##
## LEF for PtnCells ;
## created by Innovus v15.23-s045_1 on Sat Mar  7 15:15:52 2026
##

VERSION 5.8 ;

BUSBITCHARS "[]" ;
DIVIDERCHAR "/" ;

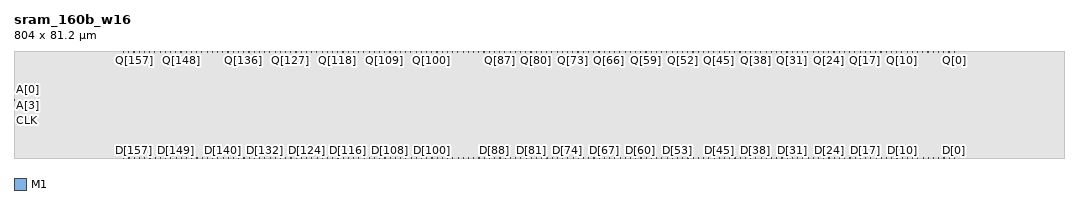
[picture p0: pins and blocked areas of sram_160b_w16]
MACRO sram_160b_w16
  CLASS BLOCK ;
  SIZE 804.0000 BY 81.2000 ;
  FOREIGN sram_160b_w16 0.0000 0.0000 ;
  ORIGIN 0 0 ;
  SYMMETRY X Y R90 ;
  PIN CLK
    DIRECTION INPUT ;
    USE SIGNAL ;
    PORT
      LAYER M1 ;
        RECT 0.0000 28.3550 0.4700 28.4450 ;
    END
  END CLK
  PIN D[159]
    DIRECTION INPUT ;
    USE SIGNAL ;
    PORT
      LAYER M1 ;
        RECT 84.0550 0.0000 84.1450 0.4700 ;
    END
  END D[159]
  PIN D[158]
    DIRECTION INPUT ;
    USE SIGNAL ;
    PORT
      LAYER M1 ;
        RECT 88.0550 0.0000 88.1450 0.4700 ;
    END
  END D[158]
  PIN D[157]
    DIRECTION INPUT ;
    USE SIGNAL ;
    PORT
      LAYER M1 ;
        RECT 92.0550 0.0000 92.1450 0.4700 ;
    END
  END D[157]
  PIN D[156]
    DIRECTION INPUT ;
    USE SIGNAL ;
    PORT
      LAYER M1 ;
        RECT 96.0550 0.0000 96.1450 0.4700 ;
    END
  END D[156]
  PIN D[155]
    DIRECTION INPUT ;
    USE SIGNAL ;
    PORT
      LAYER M1 ;
        RECT 100.0550 0.0000 100.1450 0.4700 ;
    END
  END D[155]
  PIN D[154]
    DIRECTION INPUT ;
    USE SIGNAL ;
    PORT
      LAYER M1 ;
        RECT 104.0550 0.0000 104.1450 0.4700 ;
    END
  END D[154]
  PIN D[153]
    DIRECTION INPUT ;
    USE SIGNAL ;
    PORT
      LAYER M1 ;
        RECT 108.0550 0.0000 108.1450 0.4700 ;
    END
  END D[153]
  PIN D[152]
    DIRECTION INPUT ;
    USE SIGNAL ;
    PORT
      LAYER M1 ;
        RECT 112.0550 0.0000 112.1450 0.4700 ;
    END
  END D[152]
  PIN D[151]
    DIRECTION INPUT ;
    USE SIGNAL ;
    PORT
      LAYER M1 ;
        RECT 116.0550 0.0000 116.1450 0.4700 ;
    END
  END D[151]
  PIN D[150]
    DIRECTION INPUT ;
    USE SIGNAL ;
    PORT
      LAYER M1 ;
        RECT 120.0550 0.0000 120.1450 0.4700 ;
    END
  END D[150]
  PIN D[149]
    DIRECTION INPUT ;
    USE SIGNAL ;
    PORT
      LAYER M1 ;
        RECT 124.0550 0.0000 124.1450 0.4700 ;
    END
  END D[149]
  PIN D[148]
    DIRECTION INPUT ;
    USE SIGNAL ;
    PORT
      LAYER M1 ;
        RECT 128.0550 0.0000 128.1450 0.4700 ;
    END
  END D[148]
  PIN D[147]
    DIRECTION INPUT ;
    USE SIGNAL ;
    PORT
      LAYER M1 ;
        RECT 132.0550 0.0000 132.1450 0.4700 ;
    END
  END D[147]
  PIN D[146]
    DIRECTION INPUT ;
    USE SIGNAL ;
    PORT
      LAYER M1 ;
        RECT 136.0550 0.0000 136.1450 0.4700 ;
    END
  END D[146]
  PIN D[145]
    DIRECTION INPUT ;
    USE SIGNAL ;
    PORT
      LAYER M1 ;
        RECT 140.0550 0.0000 140.1450 0.4700 ;
    END
  END D[145]
  PIN D[144]
    DIRECTION INPUT ;
    USE SIGNAL ;
    PORT
      LAYER M1 ;
        RECT 144.0550 0.0000 144.1450 0.4700 ;
    END
  END D[144]
  PIN D[143]
    DIRECTION INPUT ;
    USE SIGNAL ;
    PORT
      LAYER M1 ;
        RECT 148.0550 0.0000 148.1450 0.4700 ;
    END
  END D[143]
  PIN D[142]
    DIRECTION INPUT ;
    USE SIGNAL ;
    PORT
      LAYER M1 ;
        RECT 152.0550 0.0000 152.1450 0.4700 ;
    END
  END D[142]
  PIN D[141]
    DIRECTION INPUT ;
    USE SIGNAL ;
    PORT
      LAYER M1 ;
        RECT 156.0550 0.0000 156.1450 0.4700 ;
    END
  END D[141]
  PIN D[140]
    DIRECTION INPUT ;
    USE SIGNAL ;
    PORT
      LAYER M1 ;
        RECT 160.0550 0.0000 160.1450 0.4700 ;
    END
  END D[140]
  PIN D[139]
    DIRECTION INPUT ;
    USE SIGNAL ;
    PORT
      LAYER M1 ;
        RECT 164.0550 0.0000 164.1450 0.4700 ;
    END
  END D[139]
  PIN D[138]
    DIRECTION INPUT ;
    USE SIGNAL ;
    PORT
      LAYER M1 ;
        RECT 168.0550 0.0000 168.1450 0.4700 ;
    END
  END D[138]
  PIN D[137]
    DIRECTION INPUT ;
    USE SIGNAL ;
    PORT
      LAYER M1 ;
        RECT 172.0550 0.0000 172.1450 0.4700 ;
    END
  END D[137]
  PIN D[136]
    DIRECTION INPUT ;
    USE SIGNAL ;
    PORT
      LAYER M1 ;
        RECT 176.0550 0.0000 176.1450 0.4700 ;
    END
  END D[136]
  PIN D[135]
    DIRECTION INPUT ;
    USE SIGNAL ;
    PORT
      LAYER M1 ;
        RECT 180.0550 0.0000 180.1450 0.4700 ;
    END
  END D[135]
  PIN D[134]
    DIRECTION INPUT ;
    USE SIGNAL ;
    PORT
      LAYER M1 ;
        RECT 184.0550 0.0000 184.1450 0.4700 ;
    END
  END D[134]
  PIN D[133]
    DIRECTION INPUT ;
    USE SIGNAL ;
    PORT
      LAYER M1 ;
        RECT 188.0550 0.0000 188.1450 0.4700 ;
    END
  END D[133]
  PIN D[132]
    DIRECTION INPUT ;
    USE SIGNAL ;
    PORT
      LAYER M1 ;
        RECT 192.0550 0.0000 192.1450 0.4700 ;
    END
  END D[132]
  PIN D[131]
    DIRECTION INPUT ;
    USE SIGNAL ;
    PORT
      LAYER M1 ;
        RECT 196.0550 0.0000 196.1450 0.4700 ;
    END
  END D[131]
  PIN D[130]
    DIRECTION INPUT ;
    USE SIGNAL ;
    PORT
      LAYER M1 ;
        RECT 200.0550 0.0000 200.1450 0.4700 ;
    END
  END D[130]
  PIN D[129]
    DIRECTION INPUT ;
    USE SIGNAL ;
    PORT
      LAYER M1 ;
        RECT 204.0550 0.0000 204.1450 0.4700 ;
    END
  END D[129]
  PIN D[128]
    DIRECTION INPUT ;
    USE SIGNAL ;
    PORT
      LAYER M1 ;
        RECT 208.0550 0.0000 208.1450 0.4700 ;
    END
  END D[128]
  PIN D[127]
    DIRECTION INPUT ;
    USE SIGNAL ;
    PORT
      LAYER M1 ;
        RECT 212.0550 0.0000 212.1450 0.4700 ;
    END
  END D[127]
  PIN D[126]
    DIRECTION INPUT ;
    USE SIGNAL ;
    PORT
      LAYER M1 ;
        RECT 216.0550 0.0000 216.1450 0.4700 ;
    END
  END D[126]
  PIN D[125]
    DIRECTION INPUT ;
    USE SIGNAL ;
    PORT
      LAYER M1 ;
        RECT 220.0550 0.0000 220.1450 0.4700 ;
    END
  END D[125]
  PIN D[124]
    DIRECTION INPUT ;
    USE SIGNAL ;
    PORT
      LAYER M1 ;
        RECT 224.0550 0.0000 224.1450 0.4700 ;
    END
  END D[124]
  PIN D[123]
    DIRECTION INPUT ;
    USE SIGNAL ;
    PORT
      LAYER M1 ;
        RECT 228.0550 0.0000 228.1450 0.4700 ;
    END
  END D[123]
  PIN D[122]
    DIRECTION INPUT ;
    USE SIGNAL ;
    PORT
      LAYER M1 ;
        RECT 232.0550 0.0000 232.1450 0.4700 ;
    END
  END D[122]
  PIN D[121]
    DIRECTION INPUT ;
    USE SIGNAL ;
    PORT
      LAYER M1 ;
        RECT 236.0550 0.0000 236.1450 0.4700 ;
    END
  END D[121]
  PIN D[120]
    DIRECTION INPUT ;
    USE SIGNAL ;
    PORT
      LAYER M1 ;
        RECT 240.0550 0.0000 240.1450 0.4700 ;
    END
  END D[120]
  PIN D[119]
    DIRECTION INPUT ;
    USE SIGNAL ;
    PORT
      LAYER M1 ;
        RECT 244.0550 0.0000 244.1450 0.4700 ;
    END
  END D[119]
  PIN D[118]
    DIRECTION INPUT ;
    USE SIGNAL ;
    PORT
      LAYER M1 ;
        RECT 248.0550 0.0000 248.1450 0.4700 ;
    END
  END D[118]
  PIN D[117]
    DIRECTION INPUT ;
    USE SIGNAL ;
    PORT
      LAYER M1 ;
        RECT 252.0550 0.0000 252.1450 0.4700 ;
    END
  END D[117]
  PIN D[116]
    DIRECTION INPUT ;
    USE SIGNAL ;
    PORT
      LAYER M1 ;
        RECT 256.0550 0.0000 256.1450 0.4700 ;
    END
  END D[116]
  PIN D[115]
    DIRECTION INPUT ;
    USE SIGNAL ;
    PORT
      LAYER M1 ;
        RECT 260.0550 0.0000 260.1450 0.4700 ;
    END
  END D[115]
  PIN D[114]
    DIRECTION INPUT ;
    USE SIGNAL ;
    PORT
      LAYER M1 ;
        RECT 264.0550 0.0000 264.1450 0.4700 ;
    END
  END D[114]
  PIN D[113]
    DIRECTION INPUT ;
    USE SIGNAL ;
    PORT
      LAYER M1 ;
        RECT 268.0550 0.0000 268.1450 0.4700 ;
    END
  END D[113]
  PIN D[112]
    DIRECTION INPUT ;
    USE SIGNAL ;
    PORT
      LAYER M1 ;
        RECT 272.0550 0.0000 272.1450 0.4700 ;
    END
  END D[112]
  PIN D[111]
    DIRECTION INPUT ;
    USE SIGNAL ;
    PORT
      LAYER M1 ;
        RECT 276.0550 0.0000 276.1450 0.4700 ;
    END
  END D[111]
  PIN D[110]
    DIRECTION INPUT ;
    USE SIGNAL ;
    PORT
      LAYER M1 ;
        RECT 280.0550 0.0000 280.1450 0.4700 ;
    END
  END D[110]
  PIN D[109]
    DIRECTION INPUT ;
    USE SIGNAL ;
    PORT
      LAYER M1 ;
        RECT 284.0550 0.0000 284.1450 0.4700 ;
    END
  END D[109]
  PIN D[108]
    DIRECTION INPUT ;
    USE SIGNAL ;
    PORT
      LAYER M1 ;
        RECT 288.0550 0.0000 288.1450 0.4700 ;
    END
  END D[108]
  PIN D[107]
    DIRECTION INPUT ;
    USE SIGNAL ;
    PORT
      LAYER M1 ;
        RECT 292.0550 0.0000 292.1450 0.4700 ;
    END
  END D[107]
  PIN D[106]
    DIRECTION INPUT ;
    USE SIGNAL ;
    PORT
      LAYER M1 ;
        RECT 296.0550 0.0000 296.1450 0.4700 ;
    END
  END D[106]
  PIN D[105]
    DIRECTION INPUT ;
    USE SIGNAL ;
    PORT
      LAYER M1 ;
        RECT 300.0550 0.0000 300.1450 0.4700 ;
    END
  END D[105]
  PIN D[104]
    DIRECTION INPUT ;
    USE SIGNAL ;
    PORT
      LAYER M1 ;
        RECT 304.0550 0.0000 304.1450 0.4700 ;
    END
  END D[104]
  PIN D[103]
    DIRECTION INPUT ;
    USE SIGNAL ;
    PORT
      LAYER M1 ;
        RECT 308.0550 0.0000 308.1450 0.4700 ;
    END
  END D[103]
  PIN D[102]
    DIRECTION INPUT ;
    USE SIGNAL ;
    PORT
      LAYER M1 ;
        RECT 312.0550 0.0000 312.1450 0.4700 ;
    END
  END D[102]
  PIN D[101]
    DIRECTION INPUT ;
    USE SIGNAL ;
    PORT
      LAYER M1 ;
        RECT 316.0550 0.0000 316.1450 0.4700 ;
    END
  END D[101]
  PIN D[100]
    DIRECTION INPUT ;
    USE SIGNAL ;
    PORT
      LAYER M1 ;
        RECT 320.0550 0.0000 320.1450 0.4700 ;
    END
  END D[100]
  PIN D[99]
    DIRECTION INPUT ;
    USE SIGNAL ;
    PORT
      LAYER M1 ;
        RECT 324.0550 0.0000 324.1450 0.4700 ;
    END
  END D[99]
  PIN D[98]
    DIRECTION INPUT ;
    USE SIGNAL ;
    PORT
      LAYER M1 ;
        RECT 328.0550 0.0000 328.1450 0.4700 ;
    END
  END D[98]
  PIN D[97]
    DIRECTION INPUT ;
    USE SIGNAL ;
    PORT
      LAYER M1 ;
        RECT 332.0550 0.0000 332.1450 0.4700 ;
    END
  END D[97]
  PIN D[96]
    DIRECTION INPUT ;
    USE SIGNAL ;
    PORT
      LAYER M1 ;
        RECT 336.0550 0.0000 336.1450 0.4700 ;
    END
  END D[96]
  PIN D[95]
    DIRECTION INPUT ;
    USE SIGNAL ;
    PORT
      LAYER M1 ;
        RECT 340.0550 0.0000 340.1450 0.4700 ;
    END
  END D[95]
  PIN D[94]
    DIRECTION INPUT ;
    USE SIGNAL ;
    PORT
      LAYER M1 ;
        RECT 344.0550 0.0000 344.1450 0.4700 ;
    END
  END D[94]
  PIN D[93]
    DIRECTION INPUT ;
    USE SIGNAL ;
    PORT
      LAYER M1 ;
        RECT 348.0550 0.0000 348.1450 0.4700 ;
    END
  END D[93]
  PIN D[92]
    DIRECTION INPUT ;
    USE SIGNAL ;
    PORT
      LAYER M1 ;
        RECT 352.0550 0.0000 352.1450 0.4700 ;
    END
  END D[92]
  PIN D[91]
    DIRECTION INPUT ;
    USE SIGNAL ;
    PORT
      LAYER M1 ;
        RECT 356.0550 0.0000 356.1450 0.4700 ;
    END
  END D[91]
  PIN D[90]
    DIRECTION INPUT ;
    USE SIGNAL ;
    PORT
      LAYER M1 ;
        RECT 360.0550 0.0000 360.1450 0.4700 ;
    END
  END D[90]
  PIN D[89]
    DIRECTION INPUT ;
    USE SIGNAL ;
    PORT
      LAYER M1 ;
        RECT 364.0550 0.0000 364.1450 0.4700 ;
    END
  END D[89]
  PIN D[88]
    DIRECTION INPUT ;
    USE SIGNAL ;
    PORT
      LAYER M1 ;
        RECT 368.0550 0.0000 368.1450 0.4700 ;
    END
  END D[88]
  PIN D[87]
    DIRECTION INPUT ;
    USE SIGNAL ;
    PORT
      LAYER M1 ;
        RECT 372.0550 0.0000 372.1450 0.4700 ;
    END
  END D[87]
  PIN D[86]
    DIRECTION INPUT ;
    USE SIGNAL ;
    PORT
      LAYER M1 ;
        RECT 376.0550 0.0000 376.1450 0.4700 ;
    END
  END D[86]
  PIN D[85]
    DIRECTION INPUT ;
    USE SIGNAL ;
    PORT
      LAYER M1 ;
        RECT 380.0550 0.0000 380.1450 0.4700 ;
    END
  END D[85]
  PIN D[84]
    DIRECTION INPUT ;
    USE SIGNAL ;
    PORT
      LAYER M1 ;
        RECT 384.0550 0.0000 384.1450 0.4700 ;
    END
  END D[84]
  PIN D[83]
    DIRECTION INPUT ;
    USE SIGNAL ;
    PORT
      LAYER M1 ;
        RECT 388.0550 0.0000 388.1450 0.4700 ;
    END
  END D[83]
  PIN D[82]
    DIRECTION INPUT ;
    USE SIGNAL ;
    PORT
      LAYER M1 ;
        RECT 392.0550 0.0000 392.1450 0.4700 ;
    END
  END D[82]
  PIN D[81]
    DIRECTION INPUT ;
    USE SIGNAL ;
    PORT
      LAYER M1 ;
        RECT 396.0550 0.0000 396.1450 0.4700 ;
    END
  END D[81]
  PIN D[80]
    DIRECTION INPUT ;
    USE SIGNAL ;
    PORT
      LAYER M1 ;
        RECT 400.0550 0.0000 400.1450 0.4700 ;
    END
  END D[80]
  PIN D[79]
    DIRECTION INPUT ;
    USE SIGNAL ;
    PORT
      LAYER M1 ;
        RECT 404.0550 0.0000 404.1450 0.4700 ;
    END
  END D[79]
  PIN D[78]
    DIRECTION INPUT ;
    USE SIGNAL ;
    PORT
      LAYER M1 ;
        RECT 408.0550 0.0000 408.1450 0.4700 ;
    END
  END D[78]
  PIN D[77]
    DIRECTION INPUT ;
    USE SIGNAL ;
    PORT
      LAYER M1 ;
        RECT 412.0550 0.0000 412.1450 0.4700 ;
    END
  END D[77]
  PIN D[76]
    DIRECTION INPUT ;
    USE SIGNAL ;
    PORT
      LAYER M1 ;
        RECT 416.0550 0.0000 416.1450 0.4700 ;
    END
  END D[76]
  PIN D[75]
    DIRECTION INPUT ;
    USE SIGNAL ;
    PORT
      LAYER M1 ;
        RECT 420.0550 0.0000 420.1450 0.4700 ;
    END
  END D[75]
  PIN D[74]
    DIRECTION INPUT ;
    USE SIGNAL ;
    PORT
      LAYER M1 ;
        RECT 424.0550 0.0000 424.1450 0.4700 ;
    END
  END D[74]
  PIN D[73]
    DIRECTION INPUT ;
    USE SIGNAL ;
    PORT
      LAYER M1 ;
        RECT 428.0550 0.0000 428.1450 0.4700 ;
    END
  END D[73]
  PIN D[72]
    DIRECTION INPUT ;
    USE SIGNAL ;
    PORT
      LAYER M1 ;
        RECT 432.0550 0.0000 432.1450 0.4700 ;
    END
  END D[72]
  PIN D[71]
    DIRECTION INPUT ;
    USE SIGNAL ;
    PORT
      LAYER M1 ;
        RECT 436.0550 0.0000 436.1450 0.4700 ;
    END
  END D[71]
  PIN D[70]
    DIRECTION INPUT ;
    USE SIGNAL ;
    PORT
      LAYER M1 ;
        RECT 440.0550 0.0000 440.1450 0.4700 ;
    END
  END D[70]
  PIN D[69]
    DIRECTION INPUT ;
    USE SIGNAL ;
    PORT
      LAYER M1 ;
        RECT 444.0550 0.0000 444.1450 0.4700 ;
    END
  END D[69]
  PIN D[68]
    DIRECTION INPUT ;
    USE SIGNAL ;
    PORT
      LAYER M1 ;
        RECT 448.0550 0.0000 448.1450 0.4700 ;
    END
  END D[68]
  PIN D[67]
    DIRECTION INPUT ;
    USE SIGNAL ;
    PORT
      LAYER M1 ;
        RECT 452.0550 0.0000 452.1450 0.4700 ;
    END
  END D[67]
  PIN D[66]
    DIRECTION INPUT ;
    USE SIGNAL ;
    PORT
      LAYER M1 ;
        RECT 456.0550 0.0000 456.1450 0.4700 ;
    END
  END D[66]
  PIN D[65]
    DIRECTION INPUT ;
    USE SIGNAL ;
    PORT
      LAYER M1 ;
        RECT 460.0550 0.0000 460.1450 0.4700 ;
    END
  END D[65]
  PIN D[64]
    DIRECTION INPUT ;
    USE SIGNAL ;
    PORT
      LAYER M1 ;
        RECT 464.0550 0.0000 464.1450 0.4700 ;
    END
  END D[64]
  PIN D[63]
    DIRECTION INPUT ;
    USE SIGNAL ;
    PORT
      LAYER M1 ;
        RECT 468.0550 0.0000 468.1450 0.4700 ;
    END
  END D[63]
  PIN D[62]
    DIRECTION INPUT ;
    USE SIGNAL ;
    PORT
      LAYER M1 ;
        RECT 472.0550 0.0000 472.1450 0.4700 ;
    END
  END D[62]
  PIN D[61]
    DIRECTION INPUT ;
    USE SIGNAL ;
    PORT
      LAYER M1 ;
        RECT 476.0550 0.0000 476.1450 0.4700 ;
    END
  END D[61]
  PIN D[60]
    DIRECTION INPUT ;
    USE SIGNAL ;
    PORT
      LAYER M1 ;
        RECT 480.0550 0.0000 480.1450 0.4700 ;
    END
  END D[60]
  PIN D[59]
    DIRECTION INPUT ;
    USE SIGNAL ;
    PORT
      LAYER M1 ;
        RECT 484.0550 0.0000 484.1450 0.4700 ;
    END
  END D[59]
  PIN D[58]
    DIRECTION INPUT ;
    USE SIGNAL ;
    PORT
      LAYER M1 ;
        RECT 488.0550 0.0000 488.1450 0.4700 ;
    END
  END D[58]
  PIN D[57]
    DIRECTION INPUT ;
    USE SIGNAL ;
    PORT
      LAYER M1 ;
        RECT 492.0550 0.0000 492.1450 0.4700 ;
    END
  END D[57]
  PIN D[56]
    DIRECTION INPUT ;
    USE SIGNAL ;
    PORT
      LAYER M1 ;
        RECT 496.0550 0.0000 496.1450 0.4700 ;
    END
  END D[56]
  PIN D[55]
    DIRECTION INPUT ;
    USE SIGNAL ;
    PORT
      LAYER M1 ;
        RECT 500.0550 0.0000 500.1450 0.4700 ;
    END
  END D[55]
  PIN D[54]
    DIRECTION INPUT ;
    USE SIGNAL ;
    PORT
      LAYER M1 ;
        RECT 504.0550 0.0000 504.1450 0.4700 ;
    END
  END D[54]
  PIN D[53]
    DIRECTION INPUT ;
    USE SIGNAL ;
    PORT
      LAYER M1 ;
        RECT 508.0550 0.0000 508.1450 0.4700 ;
    END
  END D[53]
  PIN D[52]
    DIRECTION INPUT ;
    USE SIGNAL ;
    PORT
      LAYER M1 ;
        RECT 512.0550 0.0000 512.1450 0.4700 ;
    END
  END D[52]
  PIN D[51]
    DIRECTION INPUT ;
    USE SIGNAL ;
    PORT
      LAYER M1 ;
        RECT 516.0550 0.0000 516.1450 0.4700 ;
    END
  END D[51]
  PIN D[50]
    DIRECTION INPUT ;
    USE SIGNAL ;
    PORT
      LAYER M1 ;
        RECT 520.0550 0.0000 520.1450 0.4700 ;
    END
  END D[50]
  PIN D[49]
    DIRECTION INPUT ;
    USE SIGNAL ;
    PORT
      LAYER M1 ;
        RECT 524.0550 0.0000 524.1450 0.4700 ;
    END
  END D[49]
  PIN D[48]
    DIRECTION INPUT ;
    USE SIGNAL ;
    PORT
      LAYER M1 ;
        RECT 528.0550 0.0000 528.1450 0.4700 ;
    END
  END D[48]
  PIN D[47]
    DIRECTION INPUT ;
    USE SIGNAL ;
    PORT
      LAYER M1 ;
        RECT 532.0550 0.0000 532.1450 0.4700 ;
    END
  END D[47]
  PIN D[46]
    DIRECTION INPUT ;
    USE SIGNAL ;
    PORT
      LAYER M1 ;
        RECT 536.0550 0.0000 536.1450 0.4700 ;
    END
  END D[46]
  PIN D[45]
    DIRECTION INPUT ;
    USE SIGNAL ;
    PORT
      LAYER M1 ;
        RECT 540.0550 0.0000 540.1450 0.4700 ;
    END
  END D[45]
  PIN D[44]
    DIRECTION INPUT ;
    USE SIGNAL ;
    PORT
      LAYER M1 ;
        RECT 544.0550 0.0000 544.1450 0.4700 ;
    END
  END D[44]
  PIN D[43]
    DIRECTION INPUT ;
    USE SIGNAL ;
    PORT
      LAYER M1 ;
        RECT 548.0550 0.0000 548.1450 0.4700 ;
    END
  END D[43]
  PIN D[42]
    DIRECTION INPUT ;
    USE SIGNAL ;
    PORT
      LAYER M1 ;
        RECT 552.0550 0.0000 552.1450 0.4700 ;
    END
  END D[42]
  PIN D[41]
    DIRECTION INPUT ;
    USE SIGNAL ;
    PORT
      LAYER M1 ;
        RECT 556.0550 0.0000 556.1450 0.4700 ;
    END
  END D[41]
  PIN D[40]
    DIRECTION INPUT ;
    USE SIGNAL ;
    PORT
      LAYER M1 ;
        RECT 560.0550 0.0000 560.1450 0.4700 ;
    END
  END D[40]
  PIN D[39]
    DIRECTION INPUT ;
    USE SIGNAL ;
    PORT
      LAYER M1 ;
        RECT 564.0550 0.0000 564.1450 0.4700 ;
    END
  END D[39]
  PIN D[38]
    DIRECTION INPUT ;
    USE SIGNAL ;
    PORT
      LAYER M1 ;
        RECT 568.0550 0.0000 568.1450 0.4700 ;
    END
  END D[38]
  PIN D[37]
    DIRECTION INPUT ;
    USE SIGNAL ;
    PORT
      LAYER M1 ;
        RECT 572.0550 0.0000 572.1450 0.4700 ;
    END
  END D[37]
  PIN D[36]
    DIRECTION INPUT ;
    USE SIGNAL ;
    PORT
      LAYER M1 ;
        RECT 576.0550 0.0000 576.1450 0.4700 ;
    END
  END D[36]
  PIN D[35]
    DIRECTION INPUT ;
    USE SIGNAL ;
    PORT
      LAYER M1 ;
        RECT 580.0550 0.0000 580.1450 0.4700 ;
    END
  END D[35]
  PIN D[34]
    DIRECTION INPUT ;
    USE SIGNAL ;
    PORT
      LAYER M1 ;
        RECT 584.0550 0.0000 584.1450 0.4700 ;
    END
  END D[34]
  PIN D[33]
    DIRECTION INPUT ;
    USE SIGNAL ;
    PORT
      LAYER M1 ;
        RECT 588.0550 0.0000 588.1450 0.4700 ;
    END
  END D[33]
  PIN D[32]
    DIRECTION INPUT ;
    USE SIGNAL ;
    PORT
      LAYER M1 ;
        RECT 592.0550 0.0000 592.1450 0.4700 ;
    END
  END D[32]
  PIN D[31]
    DIRECTION INPUT ;
    USE SIGNAL ;
    PORT
      LAYER M1 ;
        RECT 596.0550 0.0000 596.1450 0.4700 ;
    END
  END D[31]
  PIN D[30]
    DIRECTION INPUT ;
    USE SIGNAL ;
    PORT
      LAYER M1 ;
        RECT 600.0550 0.0000 600.1450 0.4700 ;
    END
  END D[30]
  PIN D[29]
    DIRECTION INPUT ;
    USE SIGNAL ;
    PORT
      LAYER M1 ;
        RECT 604.0550 0.0000 604.1450 0.4700 ;
    END
  END D[29]
  PIN D[28]
    DIRECTION INPUT ;
    USE SIGNAL ;
    PORT
      LAYER M1 ;
        RECT 608.0550 0.0000 608.1450 0.4700 ;
    END
  END D[28]
  PIN D[27]
    DIRECTION INPUT ;
    USE SIGNAL ;
    PORT
      LAYER M1 ;
        RECT 612.0550 0.0000 612.1450 0.4700 ;
    END
  END D[27]
  PIN D[26]
    DIRECTION INPUT ;
    USE SIGNAL ;
    PORT
      LAYER M1 ;
        RECT 616.0550 0.0000 616.1450 0.4700 ;
    END
  END D[26]
  PIN D[25]
    DIRECTION INPUT ;
    USE SIGNAL ;
    PORT
      LAYER M1 ;
        RECT 620.0550 0.0000 620.1450 0.4700 ;
    END
  END D[25]
  PIN D[24]
    DIRECTION INPUT ;
    USE SIGNAL ;
    PORT
      LAYER M1 ;
        RECT 624.0550 0.0000 624.1450 0.4700 ;
    END
  END D[24]
  PIN D[23]
    DIRECTION INPUT ;
    USE SIGNAL ;
    PORT
      LAYER M1 ;
        RECT 628.0550 0.0000 628.1450 0.4700 ;
    END
  END D[23]
  PIN D[22]
    DIRECTION INPUT ;
    USE SIGNAL ;
    PORT
      LAYER M1 ;
        RECT 632.0550 0.0000 632.1450 0.4700 ;
    END
  END D[22]
  PIN D[21]
    DIRECTION INPUT ;
    USE SIGNAL ;
    PORT
      LAYER M1 ;
        RECT 636.0550 0.0000 636.1450 0.4700 ;
    END
  END D[21]
  PIN D[20]
    DIRECTION INPUT ;
    USE SIGNAL ;
    PORT
      LAYER M1 ;
        RECT 640.0550 0.0000 640.1450 0.4700 ;
    END
  END D[20]
  PIN D[19]
    DIRECTION INPUT ;
    USE SIGNAL ;
    PORT
      LAYER M1 ;
        RECT 644.0550 0.0000 644.1450 0.4700 ;
    END
  END D[19]
  PIN D[18]
    DIRECTION INPUT ;
    USE SIGNAL ;
    PORT
      LAYER M1 ;
        RECT 648.0550 0.0000 648.1450 0.4700 ;
    END
  END D[18]
  PIN D[17]
    DIRECTION INPUT ;
    USE SIGNAL ;
    PORT
      LAYER M1 ;
        RECT 652.0550 0.0000 652.1450 0.4700 ;
    END
  END D[17]
  PIN D[16]
    DIRECTION INPUT ;
    USE SIGNAL ;
    PORT
      LAYER M1 ;
        RECT 656.0550 0.0000 656.1450 0.4700 ;
    END
  END D[16]
  PIN D[15]
    DIRECTION INPUT ;
    USE SIGNAL ;
    PORT
      LAYER M1 ;
        RECT 660.0550 0.0000 660.1450 0.4700 ;
    END
  END D[15]
  PIN D[14]
    DIRECTION INPUT ;
    USE SIGNAL ;
    PORT
      LAYER M1 ;
        RECT 664.0550 0.0000 664.1450 0.4700 ;
    END
  END D[14]
  PIN D[13]
    DIRECTION INPUT ;
    USE SIGNAL ;
    PORT
      LAYER M1 ;
        RECT 668.0550 0.0000 668.1450 0.4700 ;
    END
  END D[13]
  PIN D[12]
    DIRECTION INPUT ;
    USE SIGNAL ;
    PORT
      LAYER M1 ;
        RECT 672.0550 0.0000 672.1450 0.4700 ;
    END
  END D[12]
  PIN D[11]
    DIRECTION INPUT ;
    USE SIGNAL ;
    PORT
      LAYER M1 ;
        RECT 676.0550 0.0000 676.1450 0.4700 ;
    END
  END D[11]
  PIN D[10]
    DIRECTION INPUT ;
    USE SIGNAL ;
    PORT
      LAYER M1 ;
        RECT 680.0550 0.0000 680.1450 0.4700 ;
    END
  END D[10]
  PIN D[9]
    DIRECTION INPUT ;
    USE SIGNAL ;
    PORT
      LAYER M1 ;
        RECT 684.0550 0.0000 684.1450 0.4700 ;
    END
  END D[9]
  PIN D[8]
    DIRECTION INPUT ;
    USE SIGNAL ;
    PORT
      LAYER M1 ;
        RECT 688.0550 0.0000 688.1450 0.4700 ;
    END
  END D[8]
  PIN D[7]
    DIRECTION INPUT ;
    USE SIGNAL ;
    PORT
      LAYER M1 ;
        RECT 692.0550 0.0000 692.1450 0.4700 ;
    END
  END D[7]
  PIN D[6]
    DIRECTION INPUT ;
    USE SIGNAL ;
    PORT
      LAYER M1 ;
        RECT 696.0550 0.0000 696.1450 0.4700 ;
    END
  END D[6]
  PIN D[5]
    DIRECTION INPUT ;
    USE SIGNAL ;
    PORT
      LAYER M1 ;
        RECT 700.0550 0.0000 700.1450 0.4700 ;
    END
  END D[5]
  PIN D[4]
    DIRECTION INPUT ;
    USE SIGNAL ;
    PORT
      LAYER M1 ;
        RECT 704.0550 0.0000 704.1450 0.4700 ;
    END
  END D[4]
  PIN D[3]
    DIRECTION INPUT ;
    USE SIGNAL ;
    PORT
      LAYER M1 ;
        RECT 708.0550 0.0000 708.1450 0.4700 ;
    END
  END D[3]
  PIN D[2]
    DIRECTION INPUT ;
    USE SIGNAL ;
    PORT
      LAYER M1 ;
        RECT 712.0550 0.0000 712.1450 0.4700 ;
    END
  END D[2]
  PIN D[1]
    DIRECTION INPUT ;
    USE SIGNAL ;
    PORT
      LAYER M1 ;
        RECT 716.0550 0.0000 716.1450 0.4700 ;
    END
  END D[1]
  PIN D[0]
    DIRECTION INPUT ;
    USE SIGNAL ;
    PORT
      LAYER M1 ;
        RECT 720.0550 0.0000 720.1450 0.4700 ;
    END
  END D[0]
  PIN Q[159]
    DIRECTION OUTPUT ;
    USE SIGNAL ;
    PORT
      LAYER M1 ;
        RECT 83.8550 80.7300 83.9450 81.2000 ;
    END
  END Q[159]
  PIN Q[158]
    DIRECTION OUTPUT ;
    USE SIGNAL ;
    PORT
      LAYER M1 ;
        RECT 87.8550 80.7300 87.9450 81.2000 ;
    END
  END Q[158]
  PIN Q[157]
    DIRECTION OUTPUT ;
    USE SIGNAL ;
    PORT
      LAYER M1 ;
        RECT 91.8550 80.7300 91.9450 81.2000 ;
    END
  END Q[157]
  PIN Q[156]
    DIRECTION OUTPUT ;
    USE SIGNAL ;
    PORT
      LAYER M1 ;
        RECT 95.8550 80.7300 95.9450 81.2000 ;
    END
  END Q[156]
  PIN Q[155]
    DIRECTION OUTPUT ;
    USE SIGNAL ;
    PORT
      LAYER M1 ;
        RECT 99.8550 80.7300 99.9450 81.2000 ;
    END
  END Q[155]
  PIN Q[154]
    DIRECTION OUTPUT ;
    USE SIGNAL ;
    PORT
      LAYER M1 ;
        RECT 103.8550 80.7300 103.9450 81.2000 ;
    END
  END Q[154]
  PIN Q[153]
    DIRECTION OUTPUT ;
    USE SIGNAL ;
    PORT
      LAYER M1 ;
        RECT 107.8550 80.7300 107.9450 81.2000 ;
    END
  END Q[153]
  PIN Q[152]
    DIRECTION OUTPUT ;
    USE SIGNAL ;
    PORT
      LAYER M1 ;
        RECT 111.8550 80.7300 111.9450 81.2000 ;
    END
  END Q[152]
  PIN Q[151]
    DIRECTION OUTPUT ;
    USE SIGNAL ;
    PORT
      LAYER M1 ;
        RECT 115.8550 80.7300 115.9450 81.2000 ;
    END
  END Q[151]
  PIN Q[150]
    DIRECTION OUTPUT ;
    USE SIGNAL ;
    PORT
      LAYER M1 ;
        RECT 119.8550 80.7300 119.9450 81.2000 ;
    END
  END Q[150]
  PIN Q[149]
    DIRECTION OUTPUT ;
    USE SIGNAL ;
    PORT
      LAYER M1 ;
        RECT 123.8550 80.7300 123.9450 81.2000 ;
    END
  END Q[149]
  PIN Q[148]
    DIRECTION OUTPUT ;
    USE SIGNAL ;
    PORT
      LAYER M1 ;
        RECT 127.8550 80.7300 127.9450 81.2000 ;
    END
  END Q[148]
  PIN Q[147]
    DIRECTION OUTPUT ;
    USE SIGNAL ;
    PORT
      LAYER M1 ;
        RECT 131.8550 80.7300 131.9450 81.2000 ;
    END
  END Q[147]
  PIN Q[146]
    DIRECTION OUTPUT ;
    USE SIGNAL ;
    PORT
      LAYER M1 ;
        RECT 135.8550 80.7300 135.9450 81.2000 ;
    END
  END Q[146]
  PIN Q[145]
    DIRECTION OUTPUT ;
    USE SIGNAL ;
    PORT
      LAYER M1 ;
        RECT 139.8550 80.7300 139.9450 81.2000 ;
    END
  END Q[145]
  PIN Q[144]
    DIRECTION OUTPUT ;
    USE SIGNAL ;
    PORT
      LAYER M1 ;
        RECT 143.8550 80.7300 143.9450 81.2000 ;
    END
  END Q[144]
  PIN Q[143]
    DIRECTION OUTPUT ;
    USE SIGNAL ;
    PORT
      LAYER M1 ;
        RECT 147.8550 80.7300 147.9450 81.2000 ;
    END
  END Q[143]
  PIN Q[142]
    DIRECTION OUTPUT ;
    USE SIGNAL ;
    PORT
      LAYER M1 ;
        RECT 151.8550 80.7300 151.9450 81.2000 ;
    END
  END Q[142]
  PIN Q[141]
    DIRECTION OUTPUT ;
    USE SIGNAL ;
    PORT
      LAYER M1 ;
        RECT 155.8550 80.7300 155.9450 81.2000 ;
    END
  END Q[141]
  PIN Q[140]
    DIRECTION OUTPUT ;
    USE SIGNAL ;
    PORT
      LAYER M1 ;
        RECT 159.8550 80.7300 159.9450 81.2000 ;
    END
  END Q[140]
  PIN Q[139]
    DIRECTION OUTPUT ;
    USE SIGNAL ;
    PORT
      LAYER M1 ;
        RECT 163.8550 80.7300 163.9450 81.2000 ;
    END
  END Q[139]
  PIN Q[138]
    DIRECTION OUTPUT ;
    USE SIGNAL ;
    PORT
      LAYER M1 ;
        RECT 167.8550 80.7300 167.9450 81.2000 ;
    END
  END Q[138]
  PIN Q[137]
    DIRECTION OUTPUT ;
    USE SIGNAL ;
    PORT
      LAYER M1 ;
        RECT 171.8550 80.7300 171.9450 81.2000 ;
    END
  END Q[137]
  PIN Q[136]
    DIRECTION OUTPUT ;
    USE SIGNAL ;
    PORT
      LAYER M1 ;
        RECT 175.8550 80.7300 175.9450 81.2000 ;
    END
  END Q[136]
  PIN Q[135]
    DIRECTION OUTPUT ;
    USE SIGNAL ;
    PORT
      LAYER M1 ;
        RECT 179.8550 80.7300 179.9450 81.2000 ;
    END
  END Q[135]
  PIN Q[134]
    DIRECTION OUTPUT ;
    USE SIGNAL ;
    PORT
      LAYER M1 ;
        RECT 183.8550 80.7300 183.9450 81.2000 ;
    END
  END Q[134]
  PIN Q[133]
    DIRECTION OUTPUT ;
    USE SIGNAL ;
    PORT
      LAYER M1 ;
        RECT 187.8550 80.7300 187.9450 81.2000 ;
    END
  END Q[133]
  PIN Q[132]
    DIRECTION OUTPUT ;
    USE SIGNAL ;
    PORT
      LAYER M1 ;
        RECT 191.8550 80.7300 191.9450 81.2000 ;
    END
  END Q[132]
  PIN Q[131]
    DIRECTION OUTPUT ;
    USE SIGNAL ;
    PORT
      LAYER M1 ;
        RECT 195.8550 80.7300 195.9450 81.2000 ;
    END
  END Q[131]
  PIN Q[130]
    DIRECTION OUTPUT ;
    USE SIGNAL ;
    PORT
      LAYER M1 ;
        RECT 199.8550 80.7300 199.9450 81.2000 ;
    END
  END Q[130]
  PIN Q[129]
    DIRECTION OUTPUT ;
    USE SIGNAL ;
    PORT
      LAYER M1 ;
        RECT 203.8550 80.7300 203.9450 81.2000 ;
    END
  END Q[129]
  PIN Q[128]
    DIRECTION OUTPUT ;
    USE SIGNAL ;
    PORT
      LAYER M1 ;
        RECT 207.8550 80.7300 207.9450 81.2000 ;
    END
  END Q[128]
  PIN Q[127]
    DIRECTION OUTPUT ;
    USE SIGNAL ;
    PORT
      LAYER M1 ;
        RECT 211.8550 80.7300 211.9450 81.2000 ;
    END
  END Q[127]
  PIN Q[126]
    DIRECTION OUTPUT ;
    USE SIGNAL ;
    PORT
      LAYER M1 ;
        RECT 215.8550 80.7300 215.9450 81.2000 ;
    END
  END Q[126]
  PIN Q[125]
    DIRECTION OUTPUT ;
    USE SIGNAL ;
    PORT
      LAYER M1 ;
        RECT 219.8550 80.7300 219.9450 81.2000 ;
    END
  END Q[125]
  PIN Q[124]
    DIRECTION OUTPUT ;
    USE SIGNAL ;
    PORT
      LAYER M1 ;
        RECT 223.8550 80.7300 223.9450 81.2000 ;
    END
  END Q[124]
  PIN Q[123]
    DIRECTION OUTPUT ;
    USE SIGNAL ;
    PORT
      LAYER M1 ;
        RECT 227.8550 80.7300 227.9450 81.2000 ;
    END
  END Q[123]
  PIN Q[122]
    DIRECTION OUTPUT ;
    USE SIGNAL ;
    PORT
      LAYER M1 ;
        RECT 231.8550 80.7300 231.9450 81.2000 ;
    END
  END Q[122]
  PIN Q[121]
    DIRECTION OUTPUT ;
    USE SIGNAL ;
    PORT
      LAYER M1 ;
        RECT 235.8550 80.7300 235.9450 81.2000 ;
    END
  END Q[121]
  PIN Q[120]
    DIRECTION OUTPUT ;
    USE SIGNAL ;
    PORT
      LAYER M1 ;
        RECT 239.8550 80.7300 239.9450 81.2000 ;
    END
  END Q[120]
  PIN Q[119]
    DIRECTION OUTPUT ;
    USE SIGNAL ;
    PORT
      LAYER M1 ;
        RECT 243.8550 80.7300 243.9450 81.2000 ;
    END
  END Q[119]
  PIN Q[118]
    DIRECTION OUTPUT ;
    USE SIGNAL ;
    PORT
      LAYER M1 ;
        RECT 247.8550 80.7300 247.9450 81.2000 ;
    END
  END Q[118]
  PIN Q[117]
    DIRECTION OUTPUT ;
    USE SIGNAL ;
    PORT
      LAYER M1 ;
        RECT 251.8550 80.7300 251.9450 81.2000 ;
    END
  END Q[117]
  PIN Q[116]
    DIRECTION OUTPUT ;
    USE SIGNAL ;
    PORT
      LAYER M1 ;
        RECT 255.8550 80.7300 255.9450 81.2000 ;
    END
  END Q[116]
  PIN Q[115]
    DIRECTION OUTPUT ;
    USE SIGNAL ;
    PORT
      LAYER M1 ;
        RECT 259.8550 80.7300 259.9450 81.2000 ;
    END
  END Q[115]
  PIN Q[114]
    DIRECTION OUTPUT ;
    USE SIGNAL ;
    PORT
      LAYER M1 ;
        RECT 263.8550 80.7300 263.9450 81.2000 ;
    END
  END Q[114]
  PIN Q[113]
    DIRECTION OUTPUT ;
    USE SIGNAL ;
    PORT
      LAYER M1 ;
        RECT 267.8550 80.7300 267.9450 81.2000 ;
    END
  END Q[113]
  PIN Q[112]
    DIRECTION OUTPUT ;
    USE SIGNAL ;
    PORT
      LAYER M1 ;
        RECT 271.8550 80.7300 271.9450 81.2000 ;
    END
  END Q[112]
  PIN Q[111]
    DIRECTION OUTPUT ;
    USE SIGNAL ;
    PORT
      LAYER M1 ;
        RECT 275.8550 80.7300 275.9450 81.2000 ;
    END
  END Q[111]
  PIN Q[110]
    DIRECTION OUTPUT ;
    USE SIGNAL ;
    PORT
      LAYER M1 ;
        RECT 279.8550 80.7300 279.9450 81.2000 ;
    END
  END Q[110]
  PIN Q[109]
    DIRECTION OUTPUT ;
    USE SIGNAL ;
    PORT
      LAYER M1 ;
        RECT 283.8550 80.7300 283.9450 81.2000 ;
    END
  END Q[109]
  PIN Q[108]
    DIRECTION OUTPUT ;
    USE SIGNAL ;
    PORT
      LAYER M1 ;
        RECT 287.8550 80.7300 287.9450 81.2000 ;
    END
  END Q[108]
  PIN Q[107]
    DIRECTION OUTPUT ;
    USE SIGNAL ;
    PORT
      LAYER M1 ;
        RECT 291.8550 80.7300 291.9450 81.2000 ;
    END
  END Q[107]
  PIN Q[106]
    DIRECTION OUTPUT ;
    USE SIGNAL ;
    PORT
      LAYER M1 ;
        RECT 295.8550 80.7300 295.9450 81.2000 ;
    END
  END Q[106]
  PIN Q[105]
    DIRECTION OUTPUT ;
    USE SIGNAL ;
    PORT
      LAYER M1 ;
        RECT 299.8550 80.7300 299.9450 81.2000 ;
    END
  END Q[105]
  PIN Q[104]
    DIRECTION OUTPUT ;
    USE SIGNAL ;
    PORT
      LAYER M1 ;
        RECT 303.8550 80.7300 303.9450 81.2000 ;
    END
  END Q[104]
  PIN Q[103]
    DIRECTION OUTPUT ;
    USE SIGNAL ;
    PORT
      LAYER M1 ;
        RECT 307.8550 80.7300 307.9450 81.2000 ;
    END
  END Q[103]
  PIN Q[102]
    DIRECTION OUTPUT ;
    USE SIGNAL ;
    PORT
      LAYER M1 ;
        RECT 311.8550 80.7300 311.9450 81.2000 ;
    END
  END Q[102]
  PIN Q[101]
    DIRECTION OUTPUT ;
    USE SIGNAL ;
    PORT
      LAYER M1 ;
        RECT 315.8550 80.7300 315.9450 81.2000 ;
    END
  END Q[101]
  PIN Q[100]
    DIRECTION OUTPUT ;
    USE SIGNAL ;
    PORT
      LAYER M1 ;
        RECT 319.8550 80.7300 319.9450 81.2000 ;
    END
  END Q[100]
  PIN Q[99]
    DIRECTION OUTPUT ;
    USE SIGNAL ;
    PORT
      LAYER M1 ;
        RECT 323.8550 80.7300 323.9450 81.2000 ;
    END
  END Q[99]
  PIN Q[98]
    DIRECTION OUTPUT ;
    USE SIGNAL ;
    PORT
      LAYER M1 ;
        RECT 327.8550 80.7300 327.9450 81.2000 ;
    END
  END Q[98]
  PIN Q[97]
    DIRECTION OUTPUT ;
    USE SIGNAL ;
    PORT
      LAYER M1 ;
        RECT 331.8550 80.7300 331.9450 81.2000 ;
    END
  END Q[97]
  PIN Q[96]
    DIRECTION OUTPUT ;
    USE SIGNAL ;
    PORT
      LAYER M1 ;
        RECT 335.8550 80.7300 335.9450 81.2000 ;
    END
  END Q[96]
  PIN Q[95]
    DIRECTION OUTPUT ;
    USE SIGNAL ;
    PORT
      LAYER M1 ;
        RECT 339.8550 80.7300 339.9450 81.2000 ;
    END
  END Q[95]
  PIN Q[94]
    DIRECTION OUTPUT ;
    USE SIGNAL ;
    PORT
      LAYER M1 ;
        RECT 343.8550 80.7300 343.9450 81.2000 ;
    END
  END Q[94]
  PIN Q[93]
    DIRECTION OUTPUT ;
    USE SIGNAL ;
    PORT
      LAYER M1 ;
        RECT 347.8550 80.7300 347.9450 81.2000 ;
    END
  END Q[93]
  PIN Q[92]
    DIRECTION OUTPUT ;
    USE SIGNAL ;
    PORT
      LAYER M1 ;
        RECT 351.8550 80.7300 351.9450 81.2000 ;
    END
  END Q[92]
  PIN Q[91]
    DIRECTION OUTPUT ;
    USE SIGNAL ;
    PORT
      LAYER M1 ;
        RECT 355.8550 80.7300 355.9450 81.2000 ;
    END
  END Q[91]
  PIN Q[90]
    DIRECTION OUTPUT ;
    USE SIGNAL ;
    PORT
      LAYER M1 ;
        RECT 359.8550 80.7300 359.9450 81.2000 ;
    END
  END Q[90]
  PIN Q[89]
    DIRECTION OUTPUT ;
    USE SIGNAL ;
    PORT
      LAYER M1 ;
        RECT 363.8550 80.7300 363.9450 81.2000 ;
    END
  END Q[89]
  PIN Q[88]
    DIRECTION OUTPUT ;
    USE SIGNAL ;
    PORT
      LAYER M1 ;
        RECT 367.8550 80.7300 367.9450 81.2000 ;
    END
  END Q[88]
  PIN Q[87]
    DIRECTION OUTPUT ;
    USE SIGNAL ;
    PORT
      LAYER M1 ;
        RECT 371.8550 80.7300 371.9450 81.2000 ;
    END
  END Q[87]
  PIN Q[86]
    DIRECTION OUTPUT ;
    USE SIGNAL ;
    PORT
      LAYER M1 ;
        RECT 375.8550 80.7300 375.9450 81.2000 ;
    END
  END Q[86]
  PIN Q[85]
    DIRECTION OUTPUT ;
    USE SIGNAL ;
    PORT
      LAYER M1 ;
        RECT 379.8550 80.7300 379.9450 81.2000 ;
    END
  END Q[85]
  PIN Q[84]
    DIRECTION OUTPUT ;
    USE SIGNAL ;
    PORT
      LAYER M1 ;
        RECT 383.8550 80.7300 383.9450 81.2000 ;
    END
  END Q[84]
  PIN Q[83]
    DIRECTION OUTPUT ;
    USE SIGNAL ;
    PORT
      LAYER M1 ;
        RECT 387.8550 80.7300 387.9450 81.2000 ;
    END
  END Q[83]
  PIN Q[82]
    DIRECTION OUTPUT ;
    USE SIGNAL ;
    PORT
      LAYER M1 ;
        RECT 391.8550 80.7300 391.9450 81.2000 ;
    END
  END Q[82]
  PIN Q[81]
    DIRECTION OUTPUT ;
    USE SIGNAL ;
    PORT
      LAYER M1 ;
        RECT 395.8550 80.7300 395.9450 81.2000 ;
    END
  END Q[81]
  PIN Q[80]
    DIRECTION OUTPUT ;
    USE SIGNAL ;
    PORT
      LAYER M1 ;
        RECT 399.8550 80.7300 399.9450 81.2000 ;
    END
  END Q[80]
  PIN Q[79]
    DIRECTION OUTPUT ;
    USE SIGNAL ;
    PORT
      LAYER M1 ;
        RECT 403.8550 80.7300 403.9450 81.2000 ;
    END
  END Q[79]
  PIN Q[78]
    DIRECTION OUTPUT ;
    USE SIGNAL ;
    PORT
      LAYER M1 ;
        RECT 407.8550 80.7300 407.9450 81.2000 ;
    END
  END Q[78]
  PIN Q[77]
    DIRECTION OUTPUT ;
    USE SIGNAL ;
    PORT
      LAYER M1 ;
        RECT 411.8550 80.7300 411.9450 81.2000 ;
    END
  END Q[77]
  PIN Q[76]
    DIRECTION OUTPUT ;
    USE SIGNAL ;
    PORT
      LAYER M1 ;
        RECT 415.8550 80.7300 415.9450 81.2000 ;
    END
  END Q[76]
  PIN Q[75]
    DIRECTION OUTPUT ;
    USE SIGNAL ;
    PORT
      LAYER M1 ;
        RECT 419.8550 80.7300 419.9450 81.2000 ;
    END
  END Q[75]
  PIN Q[74]
    DIRECTION OUTPUT ;
    USE SIGNAL ;
    PORT
      LAYER M1 ;
        RECT 423.8550 80.7300 423.9450 81.2000 ;
    END
  END Q[74]
  PIN Q[73]
    DIRECTION OUTPUT ;
    USE SIGNAL ;
    PORT
      LAYER M1 ;
        RECT 427.8550 80.7300 427.9450 81.2000 ;
    END
  END Q[73]
  PIN Q[72]
    DIRECTION OUTPUT ;
    USE SIGNAL ;
    PORT
      LAYER M1 ;
        RECT 431.8550 80.7300 431.9450 81.2000 ;
    END
  END Q[72]
  PIN Q[71]
    DIRECTION OUTPUT ;
    USE SIGNAL ;
    PORT
      LAYER M1 ;
        RECT 435.8550 80.7300 435.9450 81.2000 ;
    END
  END Q[71]
  PIN Q[70]
    DIRECTION OUTPUT ;
    USE SIGNAL ;
    PORT
      LAYER M1 ;
        RECT 439.8550 80.7300 439.9450 81.2000 ;
    END
  END Q[70]
  PIN Q[69]
    DIRECTION OUTPUT ;
    USE SIGNAL ;
    PORT
      LAYER M1 ;
        RECT 443.8550 80.7300 443.9450 81.2000 ;
    END
  END Q[69]
  PIN Q[68]
    DIRECTION OUTPUT ;
    USE SIGNAL ;
    PORT
      LAYER M1 ;
        RECT 447.8550 80.7300 447.9450 81.2000 ;
    END
  END Q[68]
  PIN Q[67]
    DIRECTION OUTPUT ;
    USE SIGNAL ;
    PORT
      LAYER M1 ;
        RECT 451.8550 80.7300 451.9450 81.2000 ;
    END
  END Q[67]
  PIN Q[66]
    DIRECTION OUTPUT ;
    USE SIGNAL ;
    PORT
      LAYER M1 ;
        RECT 455.8550 80.7300 455.9450 81.2000 ;
    END
  END Q[66]
  PIN Q[65]
    DIRECTION OUTPUT ;
    USE SIGNAL ;
    PORT
      LAYER M1 ;
        RECT 459.8550 80.7300 459.9450 81.2000 ;
    END
  END Q[65]
  PIN Q[64]
    DIRECTION OUTPUT ;
    USE SIGNAL ;
    PORT
      LAYER M1 ;
        RECT 463.8550 80.7300 463.9450 81.2000 ;
    END
  END Q[64]
  PIN Q[63]
    DIRECTION OUTPUT ;
    USE SIGNAL ;
    PORT
      LAYER M1 ;
        RECT 467.8550 80.7300 467.9450 81.2000 ;
    END
  END Q[63]
  PIN Q[62]
    DIRECTION OUTPUT ;
    USE SIGNAL ;
    PORT
      LAYER M1 ;
        RECT 471.8550 80.7300 471.9450 81.2000 ;
    END
  END Q[62]
  PIN Q[61]
    DIRECTION OUTPUT ;
    USE SIGNAL ;
    PORT
      LAYER M1 ;
        RECT 475.8550 80.7300 475.9450 81.2000 ;
    END
  END Q[61]
  PIN Q[60]
    DIRECTION OUTPUT ;
    USE SIGNAL ;
    PORT
      LAYER M1 ;
        RECT 479.8550 80.7300 479.9450 81.2000 ;
    END
  END Q[60]
  PIN Q[59]
    DIRECTION OUTPUT ;
    USE SIGNAL ;
    PORT
      LAYER M1 ;
        RECT 483.8550 80.7300 483.9450 81.2000 ;
    END
  END Q[59]
  PIN Q[58]
    DIRECTION OUTPUT ;
    USE SIGNAL ;
    PORT
      LAYER M1 ;
        RECT 487.8550 80.7300 487.9450 81.2000 ;
    END
  END Q[58]
  PIN Q[57]
    DIRECTION OUTPUT ;
    USE SIGNAL ;
    PORT
      LAYER M1 ;
        RECT 491.8550 80.7300 491.9450 81.2000 ;
    END
  END Q[57]
  PIN Q[56]
    DIRECTION OUTPUT ;
    USE SIGNAL ;
    PORT
      LAYER M1 ;
        RECT 495.8550 80.7300 495.9450 81.2000 ;
    END
  END Q[56]
  PIN Q[55]
    DIRECTION OUTPUT ;
    USE SIGNAL ;
    PORT
      LAYER M1 ;
        RECT 499.8550 80.7300 499.9450 81.2000 ;
    END
  END Q[55]
  PIN Q[54]
    DIRECTION OUTPUT ;
    USE SIGNAL ;
    PORT
      LAYER M1 ;
        RECT 503.8550 80.7300 503.9450 81.2000 ;
    END
  END Q[54]
  PIN Q[53]
    DIRECTION OUTPUT ;
    USE SIGNAL ;
    PORT
      LAYER M1 ;
        RECT 507.8550 80.7300 507.9450 81.2000 ;
    END
  END Q[53]
  PIN Q[52]
    DIRECTION OUTPUT ;
    USE SIGNAL ;
    PORT
      LAYER M1 ;
        RECT 511.8550 80.7300 511.9450 81.2000 ;
    END
  END Q[52]
  PIN Q[51]
    DIRECTION OUTPUT ;
    USE SIGNAL ;
    PORT
      LAYER M1 ;
        RECT 515.8550 80.7300 515.9450 81.2000 ;
    END
  END Q[51]
  PIN Q[50]
    DIRECTION OUTPUT ;
    USE SIGNAL ;
    PORT
      LAYER M1 ;
        RECT 519.8550 80.7300 519.9450 81.2000 ;
    END
  END Q[50]
  PIN Q[49]
    DIRECTION OUTPUT ;
    USE SIGNAL ;
    PORT
      LAYER M1 ;
        RECT 523.8550 80.7300 523.9450 81.2000 ;
    END
  END Q[49]
  PIN Q[48]
    DIRECTION OUTPUT ;
    USE SIGNAL ;
    PORT
      LAYER M1 ;
        RECT 527.8550 80.7300 527.9450 81.2000 ;
    END
  END Q[48]
  PIN Q[47]
    DIRECTION OUTPUT ;
    USE SIGNAL ;
    PORT
      LAYER M1 ;
        RECT 531.8550 80.7300 531.9450 81.2000 ;
    END
  END Q[47]
  PIN Q[46]
    DIRECTION OUTPUT ;
    USE SIGNAL ;
    PORT
      LAYER M1 ;
        RECT 535.8550 80.7300 535.9450 81.2000 ;
    END
  END Q[46]
  PIN Q[45]
    DIRECTION OUTPUT ;
    USE SIGNAL ;
    PORT
      LAYER M1 ;
        RECT 539.8550 80.7300 539.9450 81.2000 ;
    END
  END Q[45]
  PIN Q[44]
    DIRECTION OUTPUT ;
    USE SIGNAL ;
    PORT
      LAYER M1 ;
        RECT 543.8550 80.7300 543.9450 81.2000 ;
    END
  END Q[44]
  PIN Q[43]
    DIRECTION OUTPUT ;
    USE SIGNAL ;
    PORT
      LAYER M1 ;
        RECT 547.8550 80.7300 547.9450 81.2000 ;
    END
  END Q[43]
  PIN Q[42]
    DIRECTION OUTPUT ;
    USE SIGNAL ;
    PORT
      LAYER M1 ;
        RECT 551.8550 80.7300 551.9450 81.2000 ;
    END
  END Q[42]
  PIN Q[41]
    DIRECTION OUTPUT ;
    USE SIGNAL ;
    PORT
      LAYER M1 ;
        RECT 555.8550 80.7300 555.9450 81.2000 ;
    END
  END Q[41]
  PIN Q[40]
    DIRECTION OUTPUT ;
    USE SIGNAL ;
    PORT
      LAYER M1 ;
        RECT 559.8550 80.7300 559.9450 81.2000 ;
    END
  END Q[40]
  PIN Q[39]
    DIRECTION OUTPUT ;
    USE SIGNAL ;
    PORT
      LAYER M1 ;
        RECT 563.8550 80.7300 563.9450 81.2000 ;
    END
  END Q[39]
  PIN Q[38]
    DIRECTION OUTPUT ;
    USE SIGNAL ;
    PORT
      LAYER M1 ;
        RECT 567.8550 80.7300 567.9450 81.2000 ;
    END
  END Q[38]
  PIN Q[37]
    DIRECTION OUTPUT ;
    USE SIGNAL ;
    PORT
      LAYER M1 ;
        RECT 571.8550 80.7300 571.9450 81.2000 ;
    END
  END Q[37]
  PIN Q[36]
    DIRECTION OUTPUT ;
    USE SIGNAL ;
    PORT
      LAYER M1 ;
        RECT 575.8550 80.7300 575.9450 81.2000 ;
    END
  END Q[36]
  PIN Q[35]
    DIRECTION OUTPUT ;
    USE SIGNAL ;
    PORT
      LAYER M1 ;
        RECT 579.8550 80.7300 579.9450 81.2000 ;
    END
  END Q[35]
  PIN Q[34]
    DIRECTION OUTPUT ;
    USE SIGNAL ;
    PORT
      LAYER M1 ;
        RECT 583.8550 80.7300 583.9450 81.2000 ;
    END
  END Q[34]
  PIN Q[33]
    DIRECTION OUTPUT ;
    USE SIGNAL ;
    PORT
      LAYER M1 ;
        RECT 587.8550 80.7300 587.9450 81.2000 ;
    END
  END Q[33]
  PIN Q[32]
    DIRECTION OUTPUT ;
    USE SIGNAL ;
    PORT
      LAYER M1 ;
        RECT 591.8550 80.7300 591.9450 81.2000 ;
    END
  END Q[32]
  PIN Q[31]
    DIRECTION OUTPUT ;
    USE SIGNAL ;
    PORT
      LAYER M1 ;
        RECT 595.8550 80.7300 595.9450 81.2000 ;
    END
  END Q[31]
  PIN Q[30]
    DIRECTION OUTPUT ;
    USE SIGNAL ;
    PORT
      LAYER M1 ;
        RECT 599.8550 80.7300 599.9450 81.2000 ;
    END
  END Q[30]
  PIN Q[29]
    DIRECTION OUTPUT ;
    USE SIGNAL ;
    PORT
      LAYER M1 ;
        RECT 603.8550 80.7300 603.9450 81.2000 ;
    END
  END Q[29]
  PIN Q[28]
    DIRECTION OUTPUT ;
    USE SIGNAL ;
    PORT
      LAYER M1 ;
        RECT 607.8550 80.7300 607.9450 81.2000 ;
    END
  END Q[28]
  PIN Q[27]
    DIRECTION OUTPUT ;
    USE SIGNAL ;
    PORT
      LAYER M1 ;
        RECT 611.8550 80.7300 611.9450 81.2000 ;
    END
  END Q[27]
  PIN Q[26]
    DIRECTION OUTPUT ;
    USE SIGNAL ;
    PORT
      LAYER M1 ;
        RECT 615.8550 80.7300 615.9450 81.2000 ;
    END
  END Q[26]
  PIN Q[25]
    DIRECTION OUTPUT ;
    USE SIGNAL ;
    PORT
      LAYER M1 ;
        RECT 619.8550 80.7300 619.9450 81.2000 ;
    END
  END Q[25]
  PIN Q[24]
    DIRECTION OUTPUT ;
    USE SIGNAL ;
    PORT
      LAYER M1 ;
        RECT 623.8550 80.7300 623.9450 81.2000 ;
    END
  END Q[24]
  PIN Q[23]
    DIRECTION OUTPUT ;
    USE SIGNAL ;
    PORT
      LAYER M1 ;
        RECT 627.8550 80.7300 627.9450 81.2000 ;
    END
  END Q[23]
  PIN Q[22]
    DIRECTION OUTPUT ;
    USE SIGNAL ;
    PORT
      LAYER M1 ;
        RECT 631.8550 80.7300 631.9450 81.2000 ;
    END
  END Q[22]
  PIN Q[21]
    DIRECTION OUTPUT ;
    USE SIGNAL ;
    PORT
      LAYER M1 ;
        RECT 635.8550 80.7300 635.9450 81.2000 ;
    END
  END Q[21]
  PIN Q[20]
    DIRECTION OUTPUT ;
    USE SIGNAL ;
    PORT
      LAYER M1 ;
        RECT 639.8550 80.7300 639.9450 81.2000 ;
    END
  END Q[20]
  PIN Q[19]
    DIRECTION OUTPUT ;
    USE SIGNAL ;
    PORT
      LAYER M1 ;
        RECT 643.8550 80.7300 643.9450 81.2000 ;
    END
  END Q[19]
  PIN Q[18]
    DIRECTION OUTPUT ;
    USE SIGNAL ;
    PORT
      LAYER M1 ;
        RECT 647.8550 80.7300 647.9450 81.2000 ;
    END
  END Q[18]
  PIN Q[17]
    DIRECTION OUTPUT ;
    USE SIGNAL ;
    PORT
      LAYER M1 ;
        RECT 651.8550 80.7300 651.9450 81.2000 ;
    END
  END Q[17]
  PIN Q[16]
    DIRECTION OUTPUT ;
    USE SIGNAL ;
    PORT
      LAYER M1 ;
        RECT 655.8550 80.7300 655.9450 81.2000 ;
    END
  END Q[16]
  PIN Q[15]
    DIRECTION OUTPUT ;
    USE SIGNAL ;
    PORT
      LAYER M1 ;
        RECT 659.8550 80.7300 659.9450 81.2000 ;
    END
  END Q[15]
  PIN Q[14]
    DIRECTION OUTPUT ;
    USE SIGNAL ;
    PORT
      LAYER M1 ;
        RECT 663.8550 80.7300 663.9450 81.2000 ;
    END
  END Q[14]
  PIN Q[13]
    DIRECTION OUTPUT ;
    USE SIGNAL ;
    PORT
      LAYER M1 ;
        RECT 667.8550 80.7300 667.9450 81.2000 ;
    END
  END Q[13]
  PIN Q[12]
    DIRECTION OUTPUT ;
    USE SIGNAL ;
    PORT
      LAYER M1 ;
        RECT 671.8550 80.7300 671.9450 81.2000 ;
    END
  END Q[12]
  PIN Q[11]
    DIRECTION OUTPUT ;
    USE SIGNAL ;
    PORT
      LAYER M1 ;
        RECT 675.8550 80.7300 675.9450 81.2000 ;
    END
  END Q[11]
  PIN Q[10]
    DIRECTION OUTPUT ;
    USE SIGNAL ;
    PORT
      LAYER M1 ;
        RECT 679.8550 80.7300 679.9450 81.2000 ;
    END
  END Q[10]
  PIN Q[9]
    DIRECTION OUTPUT ;
    USE SIGNAL ;
    PORT
      LAYER M1 ;
        RECT 683.8550 80.7300 683.9450 81.2000 ;
    END
  END Q[9]
  PIN Q[8]
    DIRECTION OUTPUT ;
    USE SIGNAL ;
    PORT
      LAYER M1 ;
        RECT 687.8550 80.7300 687.9450 81.2000 ;
    END
  END Q[8]
  PIN Q[7]
    DIRECTION OUTPUT ;
    USE SIGNAL ;
    PORT
      LAYER M1 ;
        RECT 691.8550 80.7300 691.9450 81.2000 ;
    END
  END Q[7]
  PIN Q[6]
    DIRECTION OUTPUT ;
    USE SIGNAL ;
    PORT
      LAYER M1 ;
        RECT 695.8550 80.7300 695.9450 81.2000 ;
    END
  END Q[6]
  PIN Q[5]
    DIRECTION OUTPUT ;
    USE SIGNAL ;
    PORT
      LAYER M1 ;
        RECT 699.8550 80.7300 699.9450 81.2000 ;
    END
  END Q[5]
  PIN Q[4]
    DIRECTION OUTPUT ;
    USE SIGNAL ;
    PORT
      LAYER M1 ;
        RECT 703.8550 80.7300 703.9450 81.2000 ;
    END
  END Q[4]
  PIN Q[3]
    DIRECTION OUTPUT ;
    USE SIGNAL ;
    PORT
      LAYER M1 ;
        RECT 707.8550 80.7300 707.9450 81.2000 ;
    END
  END Q[3]
  PIN Q[2]
    DIRECTION OUTPUT ;
    USE SIGNAL ;
    PORT
      LAYER M1 ;
        RECT 711.8550 80.7300 711.9450 81.2000 ;
    END
  END Q[2]
  PIN Q[1]
    DIRECTION OUTPUT ;
    USE SIGNAL ;
    PORT
      LAYER M1 ;
        RECT 715.8550 80.7300 715.9450 81.2000 ;
    END
  END Q[1]
  PIN Q[0]
    DIRECTION OUTPUT ;
    USE SIGNAL ;
    PORT
      LAYER M1 ;
        RECT 719.8550 80.7300 719.9450 81.2000 ;
    END
  END Q[0]
  PIN CEN
    DIRECTION INPUT ;
    USE SIGNAL ;
    PORT
      LAYER M1 ;
        RECT 0.0000 32.3550 0.4700 32.4450 ;
    END
  END CEN
  PIN WEN
    DIRECTION INPUT ;
    USE SIGNAL ;
    PORT
      LAYER M1 ;
        RECT 0.0000 36.3550 0.4700 36.4450 ;
    END
  END WEN
  PIN A[3]
    DIRECTION INPUT ;
    USE SIGNAL ;
    PORT
      LAYER M1 ;
        RECT 0.0000 40.3550 0.4700 40.4450 ;
    END
  END A[3]
  PIN A[2]
    DIRECTION INPUT ;
    USE SIGNAL ;
    PORT
      LAYER M1 ;
        RECT 0.0000 44.3550 0.4700 44.4450 ;
    END
  END A[2]
  PIN A[1]
    DIRECTION INPUT ;
    USE SIGNAL ;
    PORT
      LAYER M1 ;
        RECT 0.0000 48.3550 0.4700 48.4450 ;
    END
  END A[1]
  PIN A[0]
    DIRECTION INPUT ;
    USE SIGNAL ;
    PORT
      LAYER M1 ;
        RECT 0.0000 52.3550 0.4700 52.4450 ;
    END
  END A[0]
  OBS
    LAYER M1 ;
      RECT 720.1050 80.5700 804.0000 81.2000 ;
      RECT 716.1050 80.5700 719.6950 81.2000 ;
      RECT 712.1050 80.5700 715.6950 81.2000 ;
      RECT 708.1050 80.5700 711.6950 81.2000 ;
      RECT 704.1050 80.5700 707.6950 81.2000 ;
      RECT 700.1050 80.5700 703.6950 81.2000 ;
      RECT 696.1050 80.5700 699.6950 81.2000 ;
      RECT 692.1050 80.5700 695.6950 81.2000 ;
      RECT 688.1050 80.5700 691.6950 81.2000 ;
      RECT 684.1050 80.5700 687.6950 81.2000 ;
      RECT 680.1050 80.5700 683.6950 81.2000 ;
      RECT 676.1050 80.5700 679.6950 81.2000 ;
      RECT 672.1050 80.5700 675.6950 81.2000 ;
      RECT 668.1050 80.5700 671.6950 81.2000 ;
      RECT 664.1050 80.5700 667.6950 81.2000 ;
      RECT 660.1050 80.5700 663.6950 81.2000 ;
      RECT 656.1050 80.5700 659.6950 81.2000 ;
      RECT 652.1050 80.5700 655.6950 81.2000 ;
      RECT 648.1050 80.5700 651.6950 81.2000 ;
      RECT 644.1050 80.5700 647.6950 81.2000 ;
      RECT 640.1050 80.5700 643.6950 81.2000 ;
      RECT 636.1050 80.5700 639.6950 81.2000 ;
      RECT 632.1050 80.5700 635.6950 81.2000 ;
      RECT 628.1050 80.5700 631.6950 81.2000 ;
      RECT 624.1050 80.5700 627.6950 81.2000 ;
      RECT 620.1050 80.5700 623.6950 81.2000 ;
      RECT 616.1050 80.5700 619.6950 81.2000 ;
      RECT 612.1050 80.5700 615.6950 81.2000 ;
      RECT 608.1050 80.5700 611.6950 81.2000 ;
      RECT 604.1050 80.5700 607.6950 81.2000 ;
      RECT 600.1050 80.5700 603.6950 81.2000 ;
      RECT 596.1050 80.5700 599.6950 81.2000 ;
      RECT 592.1050 80.5700 595.6950 81.2000 ;
      RECT 588.1050 80.5700 591.6950 81.2000 ;
      RECT 584.1050 80.5700 587.6950 81.2000 ;
      RECT 580.1050 80.5700 583.6950 81.2000 ;
      RECT 576.1050 80.5700 579.6950 81.2000 ;
      RECT 572.1050 80.5700 575.6950 81.2000 ;
      RECT 568.1050 80.5700 571.6950 81.2000 ;
      RECT 564.1050 80.5700 567.6950 81.2000 ;
      RECT 560.1050 80.5700 563.6950 81.2000 ;
      RECT 556.1050 80.5700 559.6950 81.2000 ;
      RECT 552.1050 80.5700 555.6950 81.2000 ;
      RECT 548.1050 80.5700 551.6950 81.2000 ;
      RECT 544.1050 80.5700 547.6950 81.2000 ;
      RECT 540.1050 80.5700 543.6950 81.2000 ;
      RECT 536.1050 80.5700 539.6950 81.2000 ;
      RECT 532.1050 80.5700 535.6950 81.2000 ;
      RECT 528.1050 80.5700 531.6950 81.2000 ;
      RECT 524.1050 80.5700 527.6950 81.2000 ;
      RECT 520.1050 80.5700 523.6950 81.2000 ;
      RECT 516.1050 80.5700 519.6950 81.2000 ;
      RECT 512.1050 80.5700 515.6950 81.2000 ;
      RECT 508.1050 80.5700 511.6950 81.2000 ;
      RECT 504.1050 80.5700 507.6950 81.2000 ;
      RECT 500.1050 80.5700 503.6950 81.2000 ;
      RECT 496.1050 80.5700 499.6950 81.2000 ;
      RECT 492.1050 80.5700 495.6950 81.2000 ;
      RECT 488.1050 80.5700 491.6950 81.2000 ;
      RECT 484.1050 80.5700 487.6950 81.2000 ;
      RECT 480.1050 80.5700 483.6950 81.2000 ;
      RECT 476.1050 80.5700 479.6950 81.2000 ;
      RECT 472.1050 80.5700 475.6950 81.2000 ;
      RECT 468.1050 80.5700 471.6950 81.2000 ;
      RECT 464.1050 80.5700 467.6950 81.2000 ;
      RECT 460.1050 80.5700 463.6950 81.2000 ;
      RECT 456.1050 80.5700 459.6950 81.2000 ;
      RECT 452.1050 80.5700 455.6950 81.2000 ;
      RECT 448.1050 80.5700 451.6950 81.2000 ;
      RECT 444.1050 80.5700 447.6950 81.2000 ;
      RECT 440.1050 80.5700 443.6950 81.2000 ;
      RECT 436.1050 80.5700 439.6950 81.2000 ;
      RECT 432.1050 80.5700 435.6950 81.2000 ;
      RECT 428.1050 80.5700 431.6950 81.2000 ;
      RECT 424.1050 80.5700 427.6950 81.2000 ;
      RECT 420.1050 80.5700 423.6950 81.2000 ;
      RECT 416.1050 80.5700 419.6950 81.2000 ;
      RECT 412.1050 80.5700 415.6950 81.2000 ;
      RECT 408.1050 80.5700 411.6950 81.2000 ;
      RECT 404.1050 80.5700 407.6950 81.2000 ;
      RECT 400.1050 80.5700 403.6950 81.2000 ;
      RECT 396.1050 80.5700 399.6950 81.2000 ;
      RECT 392.1050 80.5700 395.6950 81.2000 ;
      RECT 388.1050 80.5700 391.6950 81.2000 ;
      RECT 384.1050 80.5700 387.6950 81.2000 ;
      RECT 380.1050 80.5700 383.6950 81.2000 ;
      RECT 376.1050 80.5700 379.6950 81.2000 ;
      RECT 372.1050 80.5700 375.6950 81.2000 ;
      RECT 368.1050 80.5700 371.6950 81.2000 ;
      RECT 364.1050 80.5700 367.6950 81.2000 ;
      RECT 360.1050 80.5700 363.6950 81.2000 ;
      RECT 356.1050 80.5700 359.6950 81.2000 ;
      RECT 352.1050 80.5700 355.6950 81.2000 ;
      RECT 348.1050 80.5700 351.6950 81.2000 ;
      RECT 344.1050 80.5700 347.6950 81.2000 ;
      RECT 340.1050 80.5700 343.6950 81.2000 ;
      RECT 336.1050 80.5700 339.6950 81.2000 ;
      RECT 332.1050 80.5700 335.6950 81.2000 ;
      RECT 328.1050 80.5700 331.6950 81.2000 ;
      RECT 324.1050 80.5700 327.6950 81.2000 ;
      RECT 320.1050 80.5700 323.6950 81.2000 ;
      RECT 316.1050 80.5700 319.6950 81.2000 ;
      RECT 312.1050 80.5700 315.6950 81.2000 ;
      RECT 308.1050 80.5700 311.6950 81.2000 ;
      RECT 304.1050 80.5700 307.6950 81.2000 ;
      RECT 300.1050 80.5700 303.6950 81.2000 ;
      RECT 296.1050 80.5700 299.6950 81.2000 ;
      RECT 292.1050 80.5700 295.6950 81.2000 ;
      RECT 288.1050 80.5700 291.6950 81.2000 ;
      RECT 284.1050 80.5700 287.6950 81.2000 ;
      RECT 280.1050 80.5700 283.6950 81.2000 ;
      RECT 276.1050 80.5700 279.6950 81.2000 ;
      RECT 272.1050 80.5700 275.6950 81.2000 ;
      RECT 268.1050 80.5700 271.6950 81.2000 ;
      RECT 264.1050 80.5700 267.6950 81.2000 ;
      RECT 260.1050 80.5700 263.6950 81.2000 ;
      RECT 256.1050 80.5700 259.6950 81.2000 ;
      RECT 252.1050 80.5700 255.6950 81.2000 ;
      RECT 248.1050 80.5700 251.6950 81.2000 ;
      RECT 244.1050 80.5700 247.6950 81.2000 ;
      RECT 240.1050 80.5700 243.6950 81.2000 ;
      RECT 236.1050 80.5700 239.6950 81.2000 ;
      RECT 232.1050 80.5700 235.6950 81.2000 ;
      RECT 228.1050 80.5700 231.6950 81.2000 ;
      RECT 224.1050 80.5700 227.6950 81.2000 ;
      RECT 220.1050 80.5700 223.6950 81.2000 ;
      RECT 216.1050 80.5700 219.6950 81.2000 ;
      RECT 212.1050 80.5700 215.6950 81.2000 ;
      RECT 208.1050 80.5700 211.6950 81.2000 ;
      RECT 204.1050 80.5700 207.6950 81.2000 ;
      RECT 200.1050 80.5700 203.6950 81.2000 ;
      RECT 196.1050 80.5700 199.6950 81.2000 ;
      RECT 192.1050 80.5700 195.6950 81.2000 ;
      RECT 188.1050 80.5700 191.6950 81.2000 ;
      RECT 184.1050 80.5700 187.6950 81.2000 ;
      RECT 180.1050 80.5700 183.6950 81.2000 ;
      RECT 176.1050 80.5700 179.6950 81.2000 ;
      RECT 172.1050 80.5700 175.6950 81.2000 ;
      RECT 168.1050 80.5700 171.6950 81.2000 ;
      RECT 164.1050 80.5700 167.6950 81.2000 ;
      RECT 160.1050 80.5700 163.6950 81.2000 ;
      RECT 156.1050 80.5700 159.6950 81.2000 ;
      RECT 152.1050 80.5700 155.6950 81.2000 ;
      RECT 148.1050 80.5700 151.6950 81.2000 ;
      RECT 144.1050 80.5700 147.6950 81.2000 ;
      RECT 140.1050 80.5700 143.6950 81.2000 ;
      RECT 136.1050 80.5700 139.6950 81.2000 ;
      RECT 132.1050 80.5700 135.6950 81.2000 ;
      RECT 128.1050 80.5700 131.6950 81.2000 ;
      RECT 124.1050 80.5700 127.6950 81.2000 ;
      RECT 120.1050 80.5700 123.6950 81.2000 ;
      RECT 116.1050 80.5700 119.6950 81.2000 ;
      RECT 112.1050 80.5700 115.6950 81.2000 ;
      RECT 108.1050 80.5700 111.6950 81.2000 ;
      RECT 104.1050 80.5700 107.6950 81.2000 ;
      RECT 100.1050 80.5700 103.6950 81.2000 ;
      RECT 96.1050 80.5700 99.6950 81.2000 ;
      RECT 92.1050 80.5700 95.6950 81.2000 ;
      RECT 88.1050 80.5700 91.6950 81.2000 ;
      RECT 84.1050 80.5700 87.6950 81.2000 ;
      RECT 0.0000 80.5700 83.6950 81.2000 ;
      RECT 0.0000 52.5350 804.0000 80.5700 ;
      RECT 0.5600 52.2650 804.0000 52.5350 ;
      RECT 0.0000 48.5350 804.0000 52.2650 ;
      RECT 0.5600 48.2650 804.0000 48.5350 ;
      RECT 0.0000 44.5350 804.0000 48.2650 ;
      RECT 0.5600 44.2650 804.0000 44.5350 ;
      RECT 0.0000 40.5350 804.0000 44.2650 ;
      RECT 0.5600 40.2650 804.0000 40.5350 ;
      RECT 0.0000 36.5350 804.0000 40.2650 ;
      RECT 0.5600 36.2650 804.0000 36.5350 ;
      RECT 0.0000 32.5350 804.0000 36.2650 ;
      RECT 0.5600 32.2650 804.0000 32.5350 ;
      RECT 0.0000 28.5350 804.0000 32.2650 ;
      RECT 0.5600 28.2650 804.0000 28.5350 ;
      RECT 0.0000 0.6300 804.0000 28.2650 ;
      RECT 720.3050 0.0000 804.0000 0.6300 ;
      RECT 716.3050 0.0000 719.8950 0.6300 ;
      RECT 712.3050 0.0000 715.8950 0.6300 ;
      RECT 708.3050 0.0000 711.8950 0.6300 ;
      RECT 704.3050 0.0000 707.8950 0.6300 ;
      RECT 700.3050 0.0000 703.8950 0.6300 ;
      RECT 696.3050 0.0000 699.8950 0.6300 ;
      RECT 692.3050 0.0000 695.8950 0.6300 ;
      RECT 688.3050 0.0000 691.8950 0.6300 ;
      RECT 684.3050 0.0000 687.8950 0.6300 ;
      RECT 680.3050 0.0000 683.8950 0.6300 ;
      RECT 676.3050 0.0000 679.8950 0.6300 ;
      RECT 672.3050 0.0000 675.8950 0.6300 ;
      RECT 668.3050 0.0000 671.8950 0.6300 ;
      RECT 664.3050 0.0000 667.8950 0.6300 ;
      RECT 660.3050 0.0000 663.8950 0.6300 ;
      RECT 656.3050 0.0000 659.8950 0.6300 ;
      RECT 652.3050 0.0000 655.8950 0.6300 ;
      RECT 648.3050 0.0000 651.8950 0.6300 ;
      RECT 644.3050 0.0000 647.8950 0.6300 ;
      RECT 640.3050 0.0000 643.8950 0.6300 ;
      RECT 636.3050 0.0000 639.8950 0.6300 ;
      RECT 632.3050 0.0000 635.8950 0.6300 ;
      RECT 628.3050 0.0000 631.8950 0.6300 ;
      RECT 624.3050 0.0000 627.8950 0.6300 ;
      RECT 620.3050 0.0000 623.8950 0.6300 ;
      RECT 616.3050 0.0000 619.8950 0.6300 ;
      RECT 612.3050 0.0000 615.8950 0.6300 ;
      RECT 608.3050 0.0000 611.8950 0.6300 ;
      RECT 604.3050 0.0000 607.8950 0.6300 ;
      RECT 600.3050 0.0000 603.8950 0.6300 ;
      RECT 596.3050 0.0000 599.8950 0.6300 ;
      RECT 592.3050 0.0000 595.8950 0.6300 ;
      RECT 588.3050 0.0000 591.8950 0.6300 ;
      RECT 584.3050 0.0000 587.8950 0.6300 ;
      RECT 580.3050 0.0000 583.8950 0.6300 ;
      RECT 576.3050 0.0000 579.8950 0.6300 ;
      RECT 572.3050 0.0000 575.8950 0.6300 ;
      RECT 568.3050 0.0000 571.8950 0.6300 ;
      RECT 564.3050 0.0000 567.8950 0.6300 ;
      RECT 560.3050 0.0000 563.8950 0.6300 ;
      RECT 556.3050 0.0000 559.8950 0.6300 ;
      RECT 552.3050 0.0000 555.8950 0.6300 ;
      RECT 548.3050 0.0000 551.8950 0.6300 ;
      RECT 544.3050 0.0000 547.8950 0.6300 ;
      RECT 540.3050 0.0000 543.8950 0.6300 ;
      RECT 536.3050 0.0000 539.8950 0.6300 ;
      RECT 532.3050 0.0000 535.8950 0.6300 ;
      RECT 528.3050 0.0000 531.8950 0.6300 ;
      RECT 524.3050 0.0000 527.8950 0.6300 ;
      RECT 520.3050 0.0000 523.8950 0.6300 ;
      RECT 516.3050 0.0000 519.8950 0.6300 ;
      RECT 512.3050 0.0000 515.8950 0.6300 ;
      RECT 508.3050 0.0000 511.8950 0.6300 ;
      RECT 504.3050 0.0000 507.8950 0.6300 ;
      RECT 500.3050 0.0000 503.8950 0.6300 ;
      RECT 496.3050 0.0000 499.8950 0.6300 ;
      RECT 492.3050 0.0000 495.8950 0.6300 ;
      RECT 488.3050 0.0000 491.8950 0.6300 ;
      RECT 484.3050 0.0000 487.8950 0.6300 ;
      RECT 480.3050 0.0000 483.8950 0.6300 ;
      RECT 476.3050 0.0000 479.8950 0.6300 ;
      RECT 472.3050 0.0000 475.8950 0.6300 ;
      RECT 468.3050 0.0000 471.8950 0.6300 ;
      RECT 464.3050 0.0000 467.8950 0.6300 ;
      RECT 460.3050 0.0000 463.8950 0.6300 ;
      RECT 456.3050 0.0000 459.8950 0.6300 ;
      RECT 452.3050 0.0000 455.8950 0.6300 ;
      RECT 448.3050 0.0000 451.8950 0.6300 ;
      RECT 444.3050 0.0000 447.8950 0.6300 ;
      RECT 440.3050 0.0000 443.8950 0.6300 ;
      RECT 436.3050 0.0000 439.8950 0.6300 ;
      RECT 432.3050 0.0000 435.8950 0.6300 ;
      RECT 428.3050 0.0000 431.8950 0.6300 ;
      RECT 424.3050 0.0000 427.8950 0.6300 ;
      RECT 420.3050 0.0000 423.8950 0.6300 ;
      RECT 416.3050 0.0000 419.8950 0.6300 ;
      RECT 412.3050 0.0000 415.8950 0.6300 ;
      RECT 408.3050 0.0000 411.8950 0.6300 ;
      RECT 404.3050 0.0000 407.8950 0.6300 ;
      RECT 400.3050 0.0000 403.8950 0.6300 ;
      RECT 396.3050 0.0000 399.8950 0.6300 ;
      RECT 392.3050 0.0000 395.8950 0.6300 ;
      RECT 388.3050 0.0000 391.8950 0.6300 ;
      RECT 384.3050 0.0000 387.8950 0.6300 ;
      RECT 380.3050 0.0000 383.8950 0.6300 ;
      RECT 376.3050 0.0000 379.8950 0.6300 ;
      RECT 372.3050 0.0000 375.8950 0.6300 ;
      RECT 368.3050 0.0000 371.8950 0.6300 ;
      RECT 364.3050 0.0000 367.8950 0.6300 ;
      RECT 360.3050 0.0000 363.8950 0.6300 ;
      RECT 356.3050 0.0000 359.8950 0.6300 ;
      RECT 352.3050 0.0000 355.8950 0.6300 ;
      RECT 348.3050 0.0000 351.8950 0.6300 ;
      RECT 344.3050 0.0000 347.8950 0.6300 ;
      RECT 340.3050 0.0000 343.8950 0.6300 ;
      RECT 336.3050 0.0000 339.8950 0.6300 ;
      RECT 332.3050 0.0000 335.8950 0.6300 ;
      RECT 328.3050 0.0000 331.8950 0.6300 ;
      RECT 324.3050 0.0000 327.8950 0.6300 ;
      RECT 320.3050 0.0000 323.8950 0.6300 ;
      RECT 316.3050 0.0000 319.8950 0.6300 ;
      RECT 312.3050 0.0000 315.8950 0.6300 ;
      RECT 308.3050 0.0000 311.8950 0.6300 ;
      RECT 304.3050 0.0000 307.8950 0.6300 ;
      RECT 300.3050 0.0000 303.8950 0.6300 ;
      RECT 296.3050 0.0000 299.8950 0.6300 ;
      RECT 292.3050 0.0000 295.8950 0.6300 ;
      RECT 288.3050 0.0000 291.8950 0.6300 ;
      RECT 284.3050 0.0000 287.8950 0.6300 ;
      RECT 280.3050 0.0000 283.8950 0.6300 ;
      RECT 276.3050 0.0000 279.8950 0.6300 ;
      RECT 272.3050 0.0000 275.8950 0.6300 ;
      RECT 268.3050 0.0000 271.8950 0.6300 ;
      RECT 264.3050 0.0000 267.8950 0.6300 ;
      RECT 260.3050 0.0000 263.8950 0.6300 ;
      RECT 256.3050 0.0000 259.8950 0.6300 ;
      RECT 252.3050 0.0000 255.8950 0.6300 ;
      RECT 248.3050 0.0000 251.8950 0.6300 ;
      RECT 244.3050 0.0000 247.8950 0.6300 ;
      RECT 240.3050 0.0000 243.8950 0.6300 ;
      RECT 236.3050 0.0000 239.8950 0.6300 ;
      RECT 232.3050 0.0000 235.8950 0.6300 ;
      RECT 228.3050 0.0000 231.8950 0.6300 ;
      RECT 224.3050 0.0000 227.8950 0.6300 ;
      RECT 220.3050 0.0000 223.8950 0.6300 ;
      RECT 216.3050 0.0000 219.8950 0.6300 ;
      RECT 212.3050 0.0000 215.8950 0.6300 ;
      RECT 208.3050 0.0000 211.8950 0.6300 ;
      RECT 204.3050 0.0000 207.8950 0.6300 ;
      RECT 200.3050 0.0000 203.8950 0.6300 ;
      RECT 196.3050 0.0000 199.8950 0.6300 ;
      RECT 192.3050 0.0000 195.8950 0.6300 ;
      RECT 188.3050 0.0000 191.8950 0.6300 ;
      RECT 184.3050 0.0000 187.8950 0.6300 ;
      RECT 180.3050 0.0000 183.8950 0.6300 ;
      RECT 176.3050 0.0000 179.8950 0.6300 ;
      RECT 172.3050 0.0000 175.8950 0.6300 ;
      RECT 168.3050 0.0000 171.8950 0.6300 ;
      RECT 164.3050 0.0000 167.8950 0.6300 ;
      RECT 160.3050 0.0000 163.8950 0.6300 ;
      RECT 156.3050 0.0000 159.8950 0.6300 ;
      RECT 152.3050 0.0000 155.8950 0.6300 ;
      RECT 148.3050 0.0000 151.8950 0.6300 ;
      RECT 144.3050 0.0000 147.8950 0.6300 ;
      RECT 140.3050 0.0000 143.8950 0.6300 ;
      RECT 136.3050 0.0000 139.8950 0.6300 ;
      RECT 132.3050 0.0000 135.8950 0.6300 ;
      RECT 128.3050 0.0000 131.8950 0.6300 ;
      RECT 124.3050 0.0000 127.8950 0.6300 ;
      RECT 120.3050 0.0000 123.8950 0.6300 ;
      RECT 116.3050 0.0000 119.8950 0.6300 ;
      RECT 112.3050 0.0000 115.8950 0.6300 ;
      RECT 108.3050 0.0000 111.8950 0.6300 ;
      RECT 104.3050 0.0000 107.8950 0.6300 ;
      RECT 100.3050 0.0000 103.8950 0.6300 ;
      RECT 96.3050 0.0000 99.8950 0.6300 ;
      RECT 92.3050 0.0000 95.8950 0.6300 ;
      RECT 88.3050 0.0000 91.8950 0.6300 ;
      RECT 84.3050 0.0000 87.8950 0.6300 ;
      RECT 0.0000 0.0000 83.8950 0.6300 ;
    LAYER M2 ;
      RECT 0.0000 0.0000 804.0000 81.2000 ;
    LAYER M3 ;
      RECT 0.0000 0.0000 804.0000 81.2000 ;
    LAYER M4 ;
      RECT 0.0000 0.0000 804.0000 81.2000 ;
  END
END sram_160b_w16

END LIBRARY
